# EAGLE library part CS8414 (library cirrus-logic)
96 kHz Digital Audio Receiver Source: http://www.cirrus.com/en/pubs/proDatasheet/8413-4.pdf

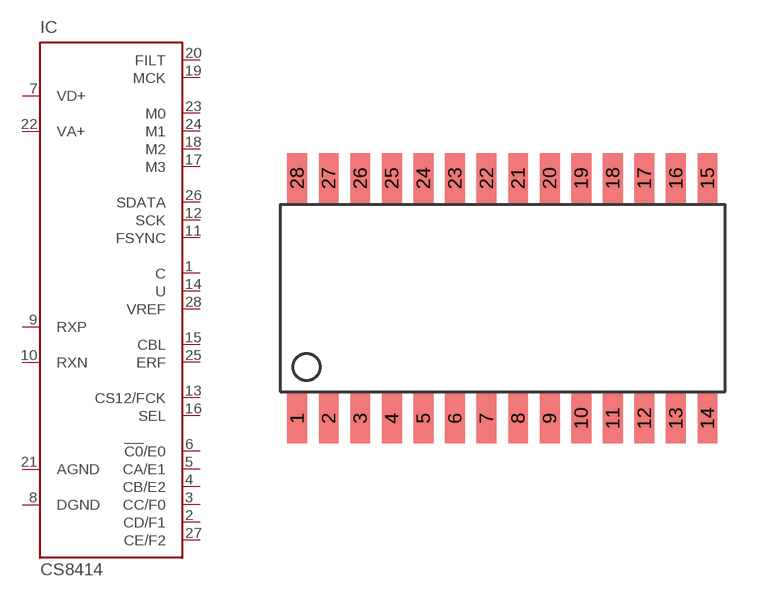
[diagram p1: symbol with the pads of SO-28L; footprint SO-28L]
Designator prefix IC

## CS8414L (MPN: CS8414-CSZR; OC_FARNELL: unknown; OC_NEWARK: 14N6027)  [SO-28L]
1  C  out
2  CD/F1  out
3  CC/F0  out
4  CB/E2  out
5  CA/E1  out
6  !C0!/E0  out
7  VD+  pwr
8  DGND  pwr
9  RXP  in
10  RXN  in
11  FSYNC
12  SCK
13  CS12/FCK  in
14  U  out
15  CBL  out
16  SEL  in
17  M3  in
18  M2  in
19  MCK
20  FILT  out
21  AGND  pwr
22  VA+  in
23  M0  in
24  M1  in
25  ERF  out
26  SDATA  out
27  CE/F2  out
28  VREF  out

## Footprint SO-28L (pad centres in mm)
Small Outline large
smd 0.8 x 2: 1 -8.255,-4.826; 2 -6.985,-4.826; 3 -5.715,-4.826; 4 -4.445,-4.826; 5 -3.175,-4.826; 6 -1.905,-4.826; 7 -0.635,-4.826; 8 0.635,-4.826; 9 1.905,-4.826; 10 3.175,-4.826; 11 4.445,-4.826; 12 5.715,-4.826; 13 6.985,-4.826; 14 8.255,-4.826; 15 8.255,4.826; 16 6.985,4.826; 17 5.715,4.826; 18 4.445,4.826; 19 3.175,4.826; 20 1.905,4.826; 21 0.635,4.826; 22 -0.635,4.826; 23 -1.905,4.826; 24 -3.175,4.826; 25 -4.445,4.826; 26 -5.715,4.826; 27 -6.985,4.826; 28 -8.255,4.826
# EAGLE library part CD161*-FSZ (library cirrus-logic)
TRIAC Dimmable LED Driver IC Source: Data sheet Reference Design

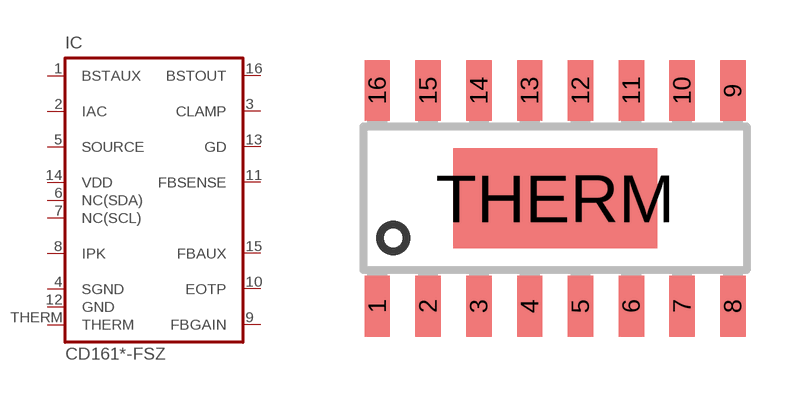
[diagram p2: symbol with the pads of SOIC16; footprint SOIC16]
Designator prefix IC

## CD1610-FSZ'' (VOLTAGE: 120VAC), CD1611-FSZ'' (VOLTAGE: 230VAC), CD1612-FSZ'' (VOLTAGE: 120VAC), CD1613-FSZ'' (VOLTAGE: 230VAC)  [SOIC16]
1  BSTAUX  in
2  IAC  in
3  CLAMP  out
4  SGND  pwr
5  SOURCE  in
6  NC(SDA)  pas
7  NC(SCL)  pas
8  IPK  in
9  FBGAIN  in
10  EOTP  in
11  FBSENSE  in
12  GND  pwr
13  GD  out
14  VDD  pwr
15  FBAUX  in
16  BSTOUT  in
THERM  THERM  pas

## Footprint SOIC16 (pad centres in mm)
16 SOICN (150 MIL BODY WITH EXPOSED PAD) Source: Data sheet
smd 0.635 x 1.524: 1 -4.445,-2.695; 2 -3.175,-2.695; 3 -1.905,-2.695; 4 -0.635,-2.695; 5 0.635,-2.695; 6 1.905,-2.695; 7 3.175,-2.695; 8 4.445,-2.695; 9 4.445,2.695; 10 3.175,2.695; 11 1.905,2.695; 12 0.635,2.695; 13 -0.635,2.695; 14 -1.905,2.695; 15 -3.175,2.695; 16 -4.445,2.695
smd 5.1 x 2.5: THERM 0,0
